VERSION 5.7 ;
BUSBITCHARS "[]" ;
DIVIDERCHAR "/" ;

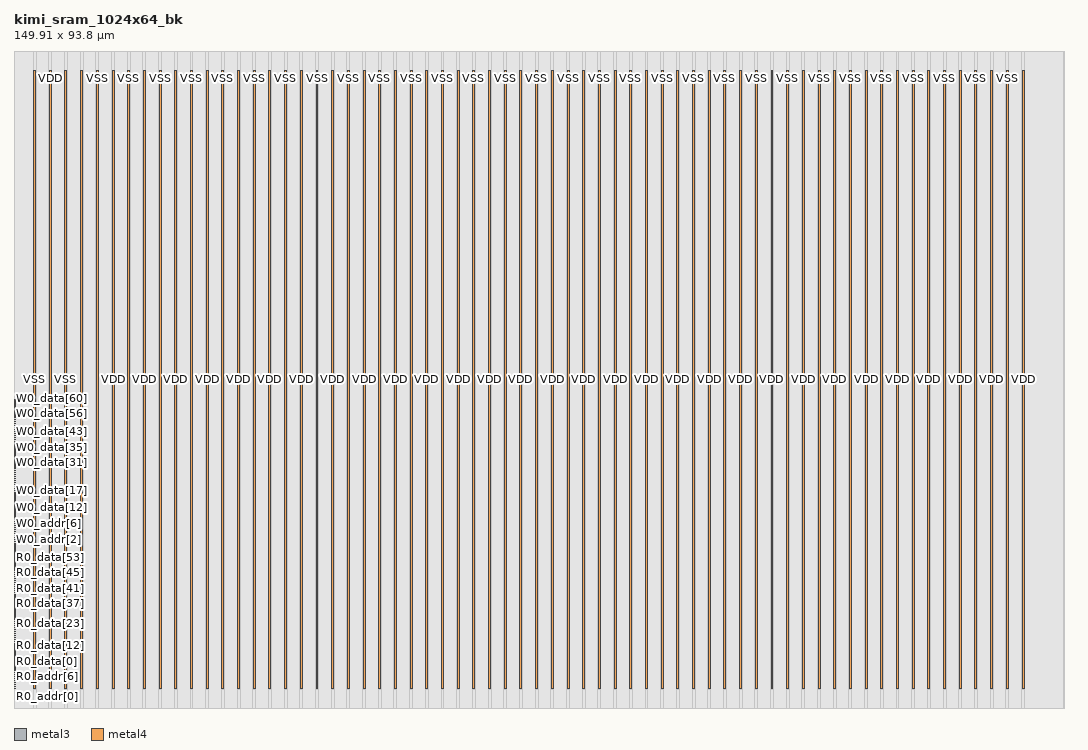
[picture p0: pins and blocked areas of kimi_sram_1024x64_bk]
MACRO kimi_sram_1024x64_bk
  CLASS BLOCK ;
  FOREIGN kimi_sram_1024x64_bk 0 0 ;
  ORIGIN 0 0 ;
  SIZE 149.91 BY 93.8 ;
  SYMMETRY X Y R90 ;
  PIN R0_addr[0]
    DIRECTION INPUT ;
    USE SIGNAL ;
    PORT
      LAYER metal3 ;
      RECT 0.0 2.765 0.19 2.835 ;
    END
  END R0_addr[0]
  PIN R0_addr[1]
    DIRECTION INPUT ;
    USE SIGNAL ;
    PORT
      LAYER metal3 ;
      RECT 0.0 3.045 0.19 3.115 ;
    END
  END R0_addr[1]
  PIN R0_addr[2]
    DIRECTION INPUT ;
    USE SIGNAL ;
    PORT
      LAYER metal3 ;
      RECT 0.0 3.325 0.19 3.395 ;
    END
  END R0_addr[2]
  PIN R0_addr[3]
    DIRECTION INPUT ;
    USE SIGNAL ;
    PORT
      LAYER metal3 ;
      RECT 0.0 3.605 0.19 3.675 ;
    END
  END R0_addr[3]
  PIN R0_addr[4]
    DIRECTION INPUT ;
    USE SIGNAL ;
    PORT
      LAYER metal3 ;
      RECT 0.0 3.885 0.19 3.955 ;
    END
  END R0_addr[4]
  PIN R0_addr[5]
    DIRECTION INPUT ;
    USE SIGNAL ;
    PORT
      LAYER metal3 ;
      RECT 0.0 4.165 0.19 4.235 ;
    END
  END R0_addr[5]
  PIN R0_addr[6]
    DIRECTION INPUT ;
    USE SIGNAL ;
    PORT
      LAYER metal3 ;
      RECT 0.0 4.445 0.19 4.515 ;
    END
  END R0_addr[6]
  PIN R0_addr[7]
    DIRECTION INPUT ;
    USE SIGNAL ;
    PORT
      LAYER metal3 ;
      RECT 0.0 4.725 0.19 4.795 ;
    END
  END R0_addr[7]
  PIN R0_clk
    DIRECTION INPUT ;
    USE SIGNAL ;
    PORT
      LAYER metal3 ;
      RECT 0.0 5.005 0.19 5.075 ;
    END
  END R0_clk
  PIN R0_en
    DIRECTION INPUT ;
    USE SIGNAL ;
    PORT
      LAYER metal3 ;
      RECT 0.0 5.285 0.19 5.355 ;
    END
  END R0_en
  PIN R0_data[0]
    DIRECTION OUTPUT ;
    USE SIGNAL ;
    PORT
      LAYER metal3 ;
      RECT 0.0 5.565 0.19 5.635 ;
    END
  END R0_data[0]
  PIN R0_data[1]
    DIRECTION OUTPUT ;
    USE SIGNAL ;
    PORT
      LAYER metal3 ;
      RECT 0.0 5.845 0.19 5.915 ;
    END
  END R0_data[1]
  PIN R0_data[2]
    DIRECTION OUTPUT ;
    USE SIGNAL ;
    PORT
      LAYER metal3 ;
      RECT 0.0 6.125 0.19 6.195 ;
    END
  END R0_data[2]
  PIN R0_data[3]
    DIRECTION OUTPUT ;
    USE SIGNAL ;
    PORT
      LAYER metal3 ;
      RECT 0.0 6.405 0.19 6.475 ;
    END
  END R0_data[3]
  PIN R0_data[4]
    DIRECTION OUTPUT ;
    USE SIGNAL ;
    PORT
      LAYER metal3 ;
      RECT 0.0 6.685 0.19 6.755 ;
    END
  END R0_data[4]
  PIN R0_data[5]
    DIRECTION OUTPUT ;
    USE SIGNAL ;
    PORT
      LAYER metal3 ;
      RECT 0.0 6.965 0.19 7.035 ;
    END
  END R0_data[5]
  PIN R0_data[6]
    DIRECTION OUTPUT ;
    USE SIGNAL ;
    PORT
      LAYER metal3 ;
      RECT 0.0 7.245 0.19 7.315 ;
    END
  END R0_data[6]
  PIN R0_data[7]
    DIRECTION OUTPUT ;
    USE SIGNAL ;
    PORT
      LAYER metal3 ;
      RECT 0.0 7.525 0.19 7.595 ;
    END
  END R0_data[7]
  PIN R0_data[8]
    DIRECTION OUTPUT ;
    USE SIGNAL ;
    PORT
      LAYER metal3 ;
      RECT 0.0 7.805 0.19 7.875 ;
    END
  END R0_data[8]
  PIN R0_data[9]
    DIRECTION OUTPUT ;
    USE SIGNAL ;
    PORT
      LAYER metal3 ;
      RECT 0.0 8.085 0.19 8.155 ;
    END
  END R0_data[9]
  PIN R0_data[10]
    DIRECTION OUTPUT ;
    USE SIGNAL ;
    PORT
      LAYER metal3 ;
      RECT 0.0 8.365 0.19 8.435 ;
    END
  END R0_data[10]
  PIN R0_data[11]
    DIRECTION OUTPUT ;
    USE SIGNAL ;
    PORT
      LAYER metal3 ;
      RECT 0.0 8.645 0.19 8.715 ;
    END
  END R0_data[11]
  PIN R0_data[12]
    DIRECTION OUTPUT ;
    USE SIGNAL ;
    PORT
      LAYER metal3 ;
      RECT 0.0 8.925 0.19 8.995 ;
    END
  END R0_data[12]
  PIN R0_data[13]
    DIRECTION OUTPUT ;
    USE SIGNAL ;
    PORT
      LAYER metal3 ;
      RECT 0.0 9.205 0.19 9.275 ;
    END
  END R0_data[13]
  PIN R0_data[14]
    DIRECTION OUTPUT ;
    USE SIGNAL ;
    PORT
      LAYER metal3 ;
      RECT 0.0 9.485 0.19 9.555 ;
    END
  END R0_data[14]
  PIN R0_data[15]
    DIRECTION OUTPUT ;
    USE SIGNAL ;
    PORT
      LAYER metal3 ;
      RECT 0.0 9.765 0.19 9.835 ;
    END
  END R0_data[15]
  PIN R0_data[16]
    DIRECTION OUTPUT ;
    USE SIGNAL ;
    PORT
      LAYER metal3 ;
      RECT 0.0 10.045 0.19 10.115 ;
    END
  END R0_data[16]
  PIN R0_data[17]
    DIRECTION OUTPUT ;
    USE SIGNAL ;
    PORT
      LAYER metal3 ;
      RECT 0.0 10.325 0.19 10.395 ;
    END
  END R0_data[17]
  PIN R0_data[18]
    DIRECTION OUTPUT ;
    USE SIGNAL ;
    PORT
      LAYER metal3 ;
      RECT 0.0 10.605 0.19 10.675 ;
    END
  END R0_data[18]
  PIN R0_data[19]
    DIRECTION OUTPUT ;
    USE SIGNAL ;
    PORT
      LAYER metal3 ;
      RECT 0.0 10.885 0.19 10.955 ;
    END
  END R0_data[19]
  PIN R0_data[20]
    DIRECTION OUTPUT ;
    USE SIGNAL ;
    PORT
      LAYER metal3 ;
      RECT 0.0 11.165 0.19 11.235 ;
    END
  END R0_data[20]
  PIN R0_data[21]
    DIRECTION OUTPUT ;
    USE SIGNAL ;
    PORT
      LAYER metal3 ;
      RECT 0.0 11.445 0.19 11.515 ;
    END
  END R0_data[21]
  PIN R0_data[22]
    DIRECTION OUTPUT ;
    USE SIGNAL ;
    PORT
      LAYER metal3 ;
      RECT 0.0 11.725 0.19 11.795 ;
    END
  END R0_data[22]
  PIN R0_data[23]
    DIRECTION OUTPUT ;
    USE SIGNAL ;
    PORT
      LAYER metal3 ;
      RECT 0.0 12.005 0.19 12.075 ;
    END
  END R0_data[23]
  PIN R0_data[24]
    DIRECTION OUTPUT ;
    USE SIGNAL ;
    PORT
      LAYER metal3 ;
      RECT 0.0 12.285 0.19 12.355 ;
    END
  END R0_data[24]
  PIN R0_data[25]
    DIRECTION OUTPUT ;
    USE SIGNAL ;
    PORT
      LAYER metal3 ;
      RECT 0.0 12.565 0.19 12.635 ;
    END
  END R0_data[25]
  PIN R0_data[26]
    DIRECTION OUTPUT ;
    USE SIGNAL ;
    PORT
      LAYER metal3 ;
      RECT 0.0 12.845 0.19 12.915 ;
    END
  END R0_data[26]
  PIN R0_data[27]
    DIRECTION OUTPUT ;
    USE SIGNAL ;
    PORT
      LAYER metal3 ;
      RECT 0.0 13.125 0.19 13.195 ;
    END
  END R0_data[27]
  PIN R0_data[28]
    DIRECTION OUTPUT ;
    USE SIGNAL ;
    PORT
      LAYER metal3 ;
      RECT 0.0 13.405 0.19 13.475 ;
    END
  END R0_data[28]
  PIN R0_data[29]
    DIRECTION OUTPUT ;
    USE SIGNAL ;
    PORT
      LAYER metal3 ;
      RECT 0.0 13.685 0.19 13.755 ;
    END
  END R0_data[29]
  PIN R0_data[30]
    DIRECTION OUTPUT ;
    USE SIGNAL ;
    PORT
      LAYER metal3 ;
      RECT 0.0 13.965 0.19 14.035 ;
    END
  END R0_data[30]
  PIN R0_data[31]
    DIRECTION OUTPUT ;
    USE SIGNAL ;
    PORT
      LAYER metal3 ;
      RECT 0.0 14.245 0.19 14.315 ;
    END
  END R0_data[31]
  PIN R0_data[32]
    DIRECTION OUTPUT ;
    USE SIGNAL ;
    PORT
      LAYER metal3 ;
      RECT 0.0 14.525 0.19 14.595 ;
    END
  END R0_data[32]
  PIN R0_data[33]
    DIRECTION OUTPUT ;
    USE SIGNAL ;
    PORT
      LAYER metal3 ;
      RECT 0.0 14.805 0.19 14.875 ;
    END
  END R0_data[33]
  PIN R0_data[34]
    DIRECTION OUTPUT ;
    USE SIGNAL ;
    PORT
      LAYER metal3 ;
      RECT 0.0 15.085 0.19 15.155 ;
    END
  END R0_data[34]
  PIN R0_data[35]
    DIRECTION OUTPUT ;
    USE SIGNAL ;
    PORT
      LAYER metal3 ;
      RECT 0.0 15.365 0.19 15.435 ;
    END
  END R0_data[35]
  PIN R0_data[36]
    DIRECTION OUTPUT ;
    USE SIGNAL ;
    PORT
      LAYER metal3 ;
      RECT 0.0 15.645 0.19 15.715 ;
    END
  END R0_data[36]
  PIN R0_data[37]
    DIRECTION OUTPUT ;
    USE SIGNAL ;
    PORT
      LAYER metal3 ;
      RECT 0.0 15.925 0.19 15.995 ;
    END
  END R0_data[37]
  PIN R0_data[38]
    DIRECTION OUTPUT ;
    USE SIGNAL ;
    PORT
      LAYER metal3 ;
      RECT 0.0 16.205 0.19 16.275 ;
    END
  END R0_data[38]
  PIN R0_data[39]
    DIRECTION OUTPUT ;
    USE SIGNAL ;
    PORT
      LAYER metal3 ;
      RECT 0.0 16.485 0.19 16.555 ;
    END
  END R0_data[39]
  PIN R0_data[40]
    DIRECTION OUTPUT ;
    USE SIGNAL ;
    PORT
      LAYER metal3 ;
      RECT 0.0 16.765 0.19 16.835 ;
    END
  END R0_data[40]
  PIN R0_data[41]
    DIRECTION OUTPUT ;
    USE SIGNAL ;
    PORT
      LAYER metal3 ;
      RECT 0.0 17.045 0.19 17.115 ;
    END
  END R0_data[41]
  PIN R0_data[42]
    DIRECTION OUTPUT ;
    USE SIGNAL ;
    PORT
      LAYER metal3 ;
      RECT 0.0 17.325 0.19 17.395 ;
    END
  END R0_data[42]
  PIN R0_data[43]
    DIRECTION OUTPUT ;
    USE SIGNAL ;
    PORT
      LAYER metal3 ;
      RECT 0.0 17.605 0.19 17.675 ;
    END
  END R0_data[43]
  PIN R0_data[44]
    DIRECTION OUTPUT ;
    USE SIGNAL ;
    PORT
      LAYER metal3 ;
      RECT 0.0 17.885 0.19 17.955 ;
    END
  END R0_data[44]
  PIN R0_data[45]
    DIRECTION OUTPUT ;
    USE SIGNAL ;
    PORT
      LAYER metal3 ;
      RECT 0.0 18.165 0.19 18.235 ;
    END
  END R0_data[45]
  PIN R0_data[46]
    DIRECTION OUTPUT ;
    USE SIGNAL ;
    PORT
      LAYER metal3 ;
      RECT 0.0 18.445 0.19 18.515 ;
    END
  END R0_data[46]
  PIN R0_data[47]
    DIRECTION OUTPUT ;
    USE SIGNAL ;
    PORT
      LAYER metal3 ;
      RECT 0.0 18.725 0.19 18.795 ;
    END
  END R0_data[47]
  PIN R0_data[48]
    DIRECTION OUTPUT ;
    USE SIGNAL ;
    PORT
      LAYER metal3 ;
      RECT 0.0 19.005 0.19 19.075 ;
    END
  END R0_data[48]
  PIN R0_data[49]
    DIRECTION OUTPUT ;
    USE SIGNAL ;
    PORT
      LAYER metal3 ;
      RECT 0.0 19.285 0.19 19.355 ;
    END
  END R0_data[49]
  PIN R0_data[50]
    DIRECTION OUTPUT ;
    USE SIGNAL ;
    PORT
      LAYER metal3 ;
      RECT 0.0 19.565 0.19 19.635 ;
    END
  END R0_data[50]
  PIN R0_data[51]
    DIRECTION OUTPUT ;
    USE SIGNAL ;
    PORT
      LAYER metal3 ;
      RECT 0.0 19.845 0.19 19.915 ;
    END
  END R0_data[51]
  PIN R0_data[52]
    DIRECTION OUTPUT ;
    USE SIGNAL ;
    PORT
      LAYER metal3 ;
      RECT 0.0 20.125 0.19 20.195 ;
    END
  END R0_data[52]
  PIN R0_data[53]
    DIRECTION OUTPUT ;
    USE SIGNAL ;
    PORT
      LAYER metal3 ;
      RECT 0.0 20.405 0.19 20.475 ;
    END
  END R0_data[53]
  PIN R0_data[54]
    DIRECTION OUTPUT ;
    USE SIGNAL ;
    PORT
      LAYER metal3 ;
      RECT 0.0 20.685 0.19 20.755 ;
    END
  END R0_data[54]
  PIN R0_data[55]
    DIRECTION OUTPUT ;
    USE SIGNAL ;
    PORT
      LAYER metal3 ;
      RECT 0.0 20.965 0.19 21.035 ;
    END
  END R0_data[55]
  PIN R0_data[56]
    DIRECTION OUTPUT ;
    USE SIGNAL ;
    PORT
      LAYER metal3 ;
      RECT 0.0 21.245 0.19 21.315 ;
    END
  END R0_data[56]
  PIN R0_data[57]
    DIRECTION OUTPUT ;
    USE SIGNAL ;
    PORT
      LAYER metal3 ;
      RECT 0.0 21.525 0.19 21.595 ;
    END
  END R0_data[57]
  PIN R0_data[58]
    DIRECTION OUTPUT ;
    USE SIGNAL ;
    PORT
      LAYER metal3 ;
      RECT 0.0 21.805 0.19 21.875 ;
    END
  END R0_data[58]
  PIN R0_data[59]
    DIRECTION OUTPUT ;
    USE SIGNAL ;
    PORT
      LAYER metal3 ;
      RECT 0.0 22.085 0.19 22.155 ;
    END
  END R0_data[59]
  PIN R0_data[60]
    DIRECTION OUTPUT ;
    USE SIGNAL ;
    PORT
      LAYER metal3 ;
      RECT 0.0 22.365 0.19 22.435 ;
    END
  END R0_data[60]
  PIN R0_data[61]
    DIRECTION OUTPUT ;
    USE SIGNAL ;
    PORT
      LAYER metal3 ;
      RECT 0.0 22.645 0.19 22.715 ;
    END
  END R0_data[61]
  PIN R0_data[62]
    DIRECTION OUTPUT ;
    USE SIGNAL ;
    PORT
      LAYER metal3 ;
      RECT 0.0 22.925 0.19 22.995 ;
    END
  END R0_data[62]
  PIN R0_data[63]
    DIRECTION OUTPUT ;
    USE SIGNAL ;
    PORT
      LAYER metal3 ;
      RECT 0.0 23.205 0.19 23.275 ;
    END
  END R0_data[63]
  PIN W0_addr[0]
    DIRECTION INPUT ;
    USE SIGNAL ;
    PORT
      LAYER metal3 ;
      RECT 0.0 23.485 0.19 23.555 ;
    END
  END W0_addr[0]
  PIN W0_addr[1]
    DIRECTION INPUT ;
    USE SIGNAL ;
    PORT
      LAYER metal3 ;
      RECT 0.0 23.765 0.19 23.835 ;
    END
  END W0_addr[1]
  PIN W0_addr[2]
    DIRECTION INPUT ;
    USE SIGNAL ;
    PORT
      LAYER metal3 ;
      RECT 0.0 24.045 0.19 24.115 ;
    END
  END W0_addr[2]
  PIN W0_addr[3]
    DIRECTION INPUT ;
    USE SIGNAL ;
    PORT
      LAYER metal3 ;
      RECT 0.0 24.325 0.19 24.395 ;
    END
  END W0_addr[3]
  PIN W0_addr[4]
    DIRECTION INPUT ;
    USE SIGNAL ;
    PORT
      LAYER metal3 ;
      RECT 0.0 24.605 0.19 24.675 ;
    END
  END W0_addr[4]
  PIN W0_addr[5]
    DIRECTION INPUT ;
    USE SIGNAL ;
    PORT
      LAYER metal3 ;
      RECT 0.0 24.885 0.19 24.955 ;
    END
  END W0_addr[5]
  PIN W0_addr[6]
    DIRECTION INPUT ;
    USE SIGNAL ;
    PORT
      LAYER metal3 ;
      RECT 0.0 25.165 0.19 25.235 ;
    END
  END W0_addr[6]
  PIN W0_addr[7]
    DIRECTION INPUT ;
    USE SIGNAL ;
    PORT
      LAYER metal3 ;
      RECT 0.0 25.445 0.19 25.515 ;
    END
  END W0_addr[7]
  PIN W0_en
    DIRECTION INPUT ;
    USE SIGNAL ;
    PORT
      LAYER metal3 ;
      RECT 0.0 25.725 0.19 25.795 ;
    END
  END W0_en
  PIN W0_clk
    DIRECTION INPUT ;
    USE SIGNAL ;
    PORT
      LAYER metal3 ;
      RECT 0.0 26.005 0.19 26.075 ;
    END
  END W0_clk
  PIN W0_data[0]
    DIRECTION INPUT ;
    USE SIGNAL ;
    PORT
      LAYER metal3 ;
      RECT 0.0 26.285 0.19 26.355 ;
    END
  END W0_data[0]
  PIN W0_data[1]
    DIRECTION INPUT ;
    USE SIGNAL ;
    PORT
      LAYER metal3 ;
      RECT 0.0 26.565 0.19 26.635 ;
    END
  END W0_data[1]
  PIN W0_data[2]
    DIRECTION INPUT ;
    USE SIGNAL ;
    PORT
      LAYER metal3 ;
      RECT 0.0 26.845 0.19 26.915 ;
    END
  END W0_data[2]
  PIN W0_data[3]
    DIRECTION INPUT ;
    USE SIGNAL ;
    PORT
      LAYER metal3 ;
      RECT 0.0 27.125 0.19 27.195 ;
    END
  END W0_data[3]
  PIN W0_data[4]
    DIRECTION INPUT ;
    USE SIGNAL ;
    PORT
      LAYER metal3 ;
      RECT 0.0 27.405 0.19 27.475 ;
    END
  END W0_data[4]
  PIN W0_data[5]
    DIRECTION INPUT ;
    USE SIGNAL ;
    PORT
      LAYER metal3 ;
      RECT 0.0 27.685 0.19 27.755 ;
    END
  END W0_data[5]
  PIN W0_data[6]
    DIRECTION INPUT ;
    USE SIGNAL ;
    PORT
      LAYER metal3 ;
      RECT 0.0 27.965 0.19 28.035 ;
    END
  END W0_data[6]
  PIN W0_data[7]
    DIRECTION INPUT ;
    USE SIGNAL ;
    PORT
      LAYER metal3 ;
      RECT 0.0 28.245 0.19 28.315 ;
    END
  END W0_data[7]
  PIN W0_data[8]
    DIRECTION INPUT ;
    USE SIGNAL ;
    PORT
      LAYER metal3 ;
      RECT 0.0 28.525 0.19 28.595 ;
    END
  END W0_data[8]
  PIN W0_data[9]
    DIRECTION INPUT ;
    USE SIGNAL ;
    PORT
      LAYER metal3 ;
      RECT 0.0 28.805 0.19 28.875 ;
    END
  END W0_data[9]
  PIN W0_data[10]
    DIRECTION INPUT ;
    USE SIGNAL ;
    PORT
      LAYER metal3 ;
      RECT 0.0 29.085 0.19 29.155 ;
    END
  END W0_data[10]
  PIN W0_data[11]
    DIRECTION INPUT ;
    USE SIGNAL ;
    PORT
      LAYER metal3 ;
      RECT 0.0 29.365 0.19 29.435 ;
    END
  END W0_data[11]
  PIN W0_data[12]
    DIRECTION INPUT ;
    USE SIGNAL ;
    PORT
      LAYER metal3 ;
      RECT 0.0 29.645 0.19 29.715 ;
    END
  END W0_data[12]
  PIN W0_data[13]
    DIRECTION INPUT ;
    USE SIGNAL ;
    PORT
      LAYER metal3 ;
      RECT 0.0 29.925 0.19 29.995 ;
    END
  END W0_data[13]
  PIN W0_data[14]
    DIRECTION INPUT ;
    USE SIGNAL ;
    PORT
      LAYER metal3 ;
      RECT 0.0 30.205 0.19 30.275 ;
    END
  END W0_data[14]
  PIN W0_data[15]
    DIRECTION INPUT ;
    USE SIGNAL ;
    PORT
      LAYER metal3 ;
      RECT 0.0 30.485 0.19 30.555 ;
    END
  END W0_data[15]
  PIN W0_data[16]
    DIRECTION INPUT ;
    USE SIGNAL ;
    PORT
      LAYER metal3 ;
      RECT 0.0 30.765 0.19 30.835 ;
    END
  END W0_data[16]
  PIN W0_data[17]
    DIRECTION INPUT ;
    USE SIGNAL ;
    PORT
      LAYER metal3 ;
      RECT 0.0 31.045 0.19 31.115 ;
    END
  END W0_data[17]
  PIN W0_data[18]
    DIRECTION INPUT ;
    USE SIGNAL ;
    PORT
      LAYER metal3 ;
      RECT 0.0 31.325 0.19 31.395 ;
    END
  END W0_data[18]
  PIN W0_data[19]
    DIRECTION INPUT ;
    USE SIGNAL ;
    PORT
      LAYER metal3 ;
      RECT 0.0 31.605 0.19 31.675 ;
    END
  END W0_data[19]
  PIN W0_data[20]
    DIRECTION INPUT ;
    USE SIGNAL ;
    PORT
      LAYER metal3 ;
      RECT 0.0 31.885 0.19 31.955 ;
    END
  END W0_data[20]
  PIN W0_data[21]
    DIRECTION INPUT ;
    USE SIGNAL ;
    PORT
      LAYER metal3 ;
      RECT 0.0 32.165 0.19 32.235 ;
    END
  END W0_data[21]
  PIN W0_data[22]
    DIRECTION INPUT ;
    USE SIGNAL ;
    PORT
      LAYER metal3 ;
      RECT 0.0 32.445 0.19 32.515 ;
    END
  END W0_data[22]
  PIN W0_data[23]
    DIRECTION INPUT ;
    USE SIGNAL ;
    PORT
      LAYER metal3 ;
      RECT 0.0 32.725 0.19 32.795 ;
    END
  END W0_data[23]
  PIN W0_data[24]
    DIRECTION INPUT ;
    USE SIGNAL ;
    PORT
      LAYER metal3 ;
      RECT 0.0 33.005 0.19 33.075 ;
    END
  END W0_data[24]
  PIN W0_data[25]
    DIRECTION INPUT ;
    USE SIGNAL ;
    PORT
      LAYER metal3 ;
      RECT 0.0 33.285 0.19 33.355 ;
    END
  END W0_data[25]
  PIN W0_data[26]
    DIRECTION INPUT ;
    USE SIGNAL ;
    PORT
      LAYER metal3 ;
      RECT 0.0 33.565 0.19 33.635 ;
    END
  END W0_data[26]
  PIN W0_data[27]
    DIRECTION INPUT ;
    USE SIGNAL ;
    PORT
      LAYER metal3 ;
      RECT 0.0 33.845 0.19 33.915 ;
    END
  END W0_data[27]
  PIN W0_data[28]
    DIRECTION INPUT ;
    USE SIGNAL ;
    PORT
      LAYER metal3 ;
      RECT 0.0 34.125 0.19 34.195 ;
    END
  END W0_data[28]
  PIN W0_data[29]
    DIRECTION INPUT ;
    USE SIGNAL ;
    PORT
      LAYER metal3 ;
      RECT 0.0 34.405 0.19 34.475 ;
    END
  END W0_data[29]
  PIN W0_data[30]
    DIRECTION INPUT ;
    USE SIGNAL ;
    PORT
      LAYER metal3 ;
      RECT 0.0 34.685 0.19 34.755 ;
    END
  END W0_data[30]
  PIN W0_data[31]
    DIRECTION INPUT ;
    USE SIGNAL ;
    PORT
      LAYER metal3 ;
      RECT 0.0 34.965 0.19 35.035 ;
    END
  END W0_data[31]
  PIN W0_data[32]
    DIRECTION INPUT ;
    USE SIGNAL ;
    PORT
      LAYER metal3 ;
      RECT 0.0 35.245 0.19 35.315 ;
    END
  END W0_data[32]
  PIN W0_data[33]
    DIRECTION INPUT ;
    USE SIGNAL ;
    PORT
      LAYER metal3 ;
      RECT 0.0 35.525 0.19 35.595 ;
    END
  END W0_data[33]
  PIN W0_data[34]
    DIRECTION INPUT ;
    USE SIGNAL ;
    PORT
      LAYER metal3 ;
      RECT 0.0 35.805 0.19 35.875 ;
    END
  END W0_data[34]
  PIN W0_data[35]
    DIRECTION INPUT ;
    USE SIGNAL ;
    PORT
      LAYER metal3 ;
      RECT 0.0 36.085 0.19 36.155 ;
    END
  END W0_data[35]
  PIN W0_data[36]
    DIRECTION INPUT ;
    USE SIGNAL ;
    PORT
      LAYER metal3 ;
      RECT 0.0 36.365 0.19 36.435 ;
    END
  END W0_data[36]
  PIN W0_data[37]
    DIRECTION INPUT ;
    USE SIGNAL ;
    PORT
      LAYER metal3 ;
      RECT 0.0 36.645 0.19 36.715 ;
    END
  END W0_data[37]
  PIN W0_data[38]
    DIRECTION INPUT ;
    USE SIGNAL ;
    PORT
      LAYER metal3 ;
      RECT 0.0 36.925 0.19 36.995 ;
    END
  END W0_data[38]
  PIN W0_data[39]
    DIRECTION INPUT ;
    USE SIGNAL ;
    PORT
      LAYER metal3 ;
      RECT 0.0 37.205 0.19 37.275 ;
    END
  END W0_data[39]
  PIN W0_data[40]
    DIRECTION INPUT ;
    USE SIGNAL ;
    PORT
      LAYER metal3 ;
      RECT 0.0 37.485 0.19 37.555 ;
    END
  END W0_data[40]
  PIN W0_data[41]
    DIRECTION INPUT ;
    USE SIGNAL ;
    PORT
      LAYER metal3 ;
      RECT 0.0 37.765 0.19 37.835 ;
    END
  END W0_data[41]
  PIN W0_data[42]
    DIRECTION INPUT ;
    USE SIGNAL ;
    PORT
      LAYER metal3 ;
      RECT 0.0 38.045 0.19 38.115 ;
    END
  END W0_data[42]
  PIN W0_data[43]
    DIRECTION INPUT ;
    USE SIGNAL ;
    PORT
      LAYER metal3 ;
      RECT 0.0 38.325 0.19 38.395 ;
    END
  END W0_data[43]
  PIN W0_data[44]
    DIRECTION INPUT ;
    USE SIGNAL ;
    PORT
      LAYER metal3 ;
      RECT 0.0 38.605 0.19 38.675 ;
    END
  END W0_data[44]
  PIN W0_data[45]
    DIRECTION INPUT ;
    USE SIGNAL ;
    PORT
      LAYER metal3 ;
      RECT 0.0 38.885 0.19 38.955 ;
    END
  END W0_data[45]
  PIN W0_data[46]
    DIRECTION INPUT ;
    USE SIGNAL ;
    PORT
      LAYER metal3 ;
      RECT 0.0 39.165 0.19 39.235 ;
    END
  END W0_data[46]
  PIN W0_data[47]
    DIRECTION INPUT ;
    USE SIGNAL ;
    PORT
      LAYER metal3 ;
      RECT 0.0 39.445 0.19 39.515 ;
    END
  END W0_data[47]
  PIN W0_data[48]
    DIRECTION INPUT ;
    USE SIGNAL ;
    PORT
      LAYER metal3 ;
      RECT 0.0 39.725 0.19 39.795 ;
    END
  END W0_data[48]
  PIN W0_data[49]
    DIRECTION INPUT ;
    USE SIGNAL ;
    PORT
      LAYER metal3 ;
      RECT 0.0 40.005 0.19 40.075 ;
    END
  END W0_data[49]
  PIN W0_data[50]
    DIRECTION INPUT ;
    USE SIGNAL ;
    PORT
      LAYER metal3 ;
      RECT 0.0 40.285 0.19 40.355 ;
    END
  END W0_data[50]
  PIN W0_data[51]
    DIRECTION INPUT ;
    USE SIGNAL ;
    PORT
      LAYER metal3 ;
      RECT 0.0 40.565 0.19 40.635 ;
    END
  END W0_data[51]
  PIN W0_data[52]
    DIRECTION INPUT ;
    USE SIGNAL ;
    PORT
      LAYER metal3 ;
      RECT 0.0 40.845 0.19 40.915 ;
    END
  END W0_data[52]
  PIN W0_data[53]
    DIRECTION INPUT ;
    USE SIGNAL ;
    PORT
      LAYER metal3 ;
      RECT 0.0 41.125 0.19 41.195 ;
    END
  END W0_data[53]
  PIN W0_data[54]
    DIRECTION INPUT ;
    USE SIGNAL ;
    PORT
      LAYER metal3 ;
      RECT 0.0 41.405 0.19 41.475 ;
    END
  END W0_data[54]
  PIN W0_data[55]
    DIRECTION INPUT ;
    USE SIGNAL ;
    PORT
      LAYER metal3 ;
      RECT 0.0 41.685 0.19 41.755 ;
    END
  END W0_data[55]
  PIN W0_data[56]
    DIRECTION INPUT ;
    USE SIGNAL ;
    PORT
      LAYER metal3 ;
      RECT 0.0 41.965 0.19 42.035 ;
    END
  END W0_data[56]
  PIN W0_data[57]
    DIRECTION INPUT ;
    USE SIGNAL ;
    PORT
      LAYER metal3 ;
      RECT 0.0 42.245 0.19 42.315 ;
    END
  END W0_data[57]
  PIN W0_data[58]
    DIRECTION INPUT ;
    USE SIGNAL ;
    PORT
      LAYER metal3 ;
      RECT 0.0 42.525 0.19 42.595 ;
    END
  END W0_data[58]
  PIN W0_data[59]
    DIRECTION INPUT ;
    USE SIGNAL ;
    PORT
      LAYER metal3 ;
      RECT 0.0 42.805 0.19 42.875 ;
    END
  END W0_data[59]
  PIN W0_data[60]
    DIRECTION INPUT ;
    USE SIGNAL ;
    PORT
      LAYER metal3 ;
      RECT 0.0 43.085 0.19 43.155 ;
    END
  END W0_data[60]
  PIN W0_data[61]
    DIRECTION INPUT ;
    USE SIGNAL ;
    PORT
      LAYER metal3 ;
      RECT 0.0 43.365 0.19 43.435 ;
    END
  END W0_data[61]
  PIN W0_data[62]
    DIRECTION INPUT ;
    USE SIGNAL ;
    PORT
      LAYER metal3 ;
      RECT 0.0 43.645 0.19 43.715 ;
    END
  END W0_data[62]
  PIN W0_data[63]
    DIRECTION INPUT ;
    USE SIGNAL ;
    PORT
      LAYER metal3 ;
      RECT 0.0 43.925 0.19 43.995 ;
    END
  END W0_data[63]
  PIN VSS
    DIRECTION INOUT ;
    USE GROUND ;
    PORT
      LAYER metal4 ;
      RECT 2.8 2.8 3.08 91.0 ;
    END
  END VSS
  PIN VDD
    DIRECTION INOUT ;
    USE POWER ;
    PORT
      LAYER metal4 ;
      RECT 5.04 2.8 5.32 91.0 ;
    END
  END VDD
  PIN VSS
    DIRECTION INOUT ;
    USE GROUND ;
    PORT
      LAYER metal4 ;
      RECT 7.28 2.8 7.56 91.0 ;
    END
  END VSS
  PIN VDD
    DIRECTION INOUT ;
    USE POWER ;
    PORT
      LAYER metal4 ;
      RECT 9.52 2.8 9.8 91.0 ;
    END
  END VDD
  PIN VSS
    DIRECTION INOUT ;
    USE GROUND ;
    PORT
      LAYER metal4 ;
      RECT 11.76 2.8 12.04 91.0 ;
    END
  END VSS
  PIN VDD
    DIRECTION INOUT ;
    USE POWER ;
    PORT
      LAYER metal4 ;
      RECT 14.0 2.8 14.28 91.0 ;
    END
  END VDD
  PIN VSS
    DIRECTION INOUT ;
    USE GROUND ;
    PORT
      LAYER metal4 ;
      RECT 16.24 2.8 16.52 91.0 ;
    END
  END VSS
  PIN VDD
    DIRECTION INOUT ;
    USE POWER ;
    PORT
      LAYER metal4 ;
      RECT 18.48 2.8 18.76 91.0 ;
    END
  END VDD
  PIN VSS
    DIRECTION INOUT ;
    USE GROUND ;
    PORT
      LAYER metal4 ;
      RECT 20.72 2.8 21.0 91.0 ;
    END
  END VSS
  PIN VDD
    DIRECTION INOUT ;
    USE POWER ;
    PORT
      LAYER metal4 ;
      RECT 22.96 2.8 23.24 91.0 ;
    END
  END VDD
  PIN VSS
    DIRECTION INOUT ;
    USE GROUND ;
    PORT
      LAYER metal4 ;
      RECT 25.2 2.8 25.48 91.0 ;
    END
  END VSS
  PIN VDD
    DIRECTION INOUT ;
    USE POWER ;
    PORT
      LAYER metal4 ;
      RECT 27.44 2.8 27.72 91.0 ;
    END
  END VDD
  PIN VSS
    DIRECTION INOUT ;
    USE GROUND ;
    PORT
      LAYER metal4 ;
      RECT 29.68 2.8 29.96 91.0 ;
    END
  END VSS
  PIN VDD
    DIRECTION INOUT ;
    USE POWER ;
    PORT
      LAYER metal4 ;
      RECT 31.92 2.8 32.2 91.0 ;
    END
  END VDD
  PIN VSS
    DIRECTION INOUT ;
    USE GROUND ;
    PORT
      LAYER metal4 ;
      RECT 34.16 2.8 34.44 91.0 ;
    END
  END VSS
  PIN VDD
    DIRECTION INOUT ;
    USE POWER ;
    PORT
      LAYER metal4 ;
      RECT 36.4 2.8 36.68 91.0 ;
    END
  END VDD
  PIN VSS
    DIRECTION INOUT ;
    USE GROUND ;
    PORT
      LAYER metal4 ;
      RECT 38.64 2.8 38.92 91.0 ;
    END
  END VSS
  PIN VDD
    DIRECTION INOUT ;
    USE POWER ;
    PORT
      LAYER metal4 ;
      RECT 40.88 2.8 41.16 91.0 ;
    END
  END VDD
  PIN VSS
    DIRECTION INOUT ;
    USE GROUND ;
    PORT
      LAYER metal4 ;
      RECT 43.12 2.8 43.4 91.0 ;
    END
  END VSS
  PIN VDD
    DIRECTION INOUT ;
    USE POWER ;
    PORT
      LAYER metal4 ;
      RECT 45.36 2.8 45.64 91.0 ;
    END
  END VDD
  PIN VSS
    DIRECTION INOUT ;
    USE GROUND ;
    PORT
      LAYER metal4 ;
      RECT 47.6 2.8 47.88 91.0 ;
    END
  END VSS
  PIN VDD
    DIRECTION INOUT ;
    USE POWER ;
    PORT
      LAYER metal4 ;
      RECT 49.84 2.8 50.12 91.0 ;
    END
  END VDD
  PIN VSS
    DIRECTION INOUT ;
    USE GROUND ;
    PORT
      LAYER metal4 ;
      RECT 52.08 2.8 52.36 91.0 ;
    END
  END VSS
  PIN VDD
    DIRECTION INOUT ;
    USE POWER ;
    PORT
      LAYER metal4 ;
      RECT 54.32 2.8 54.6 91.0 ;
    END
  END VDD
  PIN VSS
    DIRECTION INOUT ;
    USE GROUND ;
    PORT
      LAYER metal4 ;
      RECT 56.56 2.8 56.84 91.0 ;
    END
  END VSS
  PIN VDD
    DIRECTION INOUT ;
    USE POWER ;
    PORT
      LAYER metal4 ;
      RECT 58.8 2.8 59.08 91.0 ;
    END
  END VDD
  PIN VSS
    DIRECTION INOUT ;
    USE GROUND ;
    PORT
      LAYER metal4 ;
      RECT 61.04 2.8 61.32 91.0 ;
    END
  END VSS
  PIN VDD
    DIRECTION INOUT ;
    USE POWER ;
    PORT
      LAYER metal4 ;
      RECT 63.28 2.8 63.56 91.0 ;
    END
  END VDD
  PIN VSS
    DIRECTION INOUT ;
    USE GROUND ;
    PORT
      LAYER metal4 ;
      RECT 65.52 2.8 65.8 91.0 ;
    END
  END VSS
  PIN VDD
    DIRECTION INOUT ;
    USE POWER ;
    PORT
      LAYER metal4 ;
      RECT 67.76 2.8 68.04 91.0 ;
    END
  END VDD
  PIN VSS
    DIRECTION INOUT ;
    USE GROUND ;
    PORT
      LAYER metal4 ;
      RECT 70.0 2.8 70.28 91.0 ;
    END
  END VSS
  PIN VDD
    DIRECTION INOUT ;
    USE POWER ;
    PORT
      LAYER metal4 ;
      RECT 72.24 2.8 72.52 91.0 ;
    END
  END VDD
  PIN VSS
    DIRECTION INOUT ;
    USE GROUND ;
    PORT
      LAYER metal4 ;
      RECT 74.48 2.8 74.76 91.0 ;
    END
  END VSS
  PIN VDD
    DIRECTION INOUT ;
    USE POWER ;
    PORT
      LAYER metal4 ;
      RECT 76.72 2.8 77.0 91.0 ;
    END
  END VDD
  PIN VSS
    DIRECTION INOUT ;
    USE GROUND ;
    PORT
      LAYER metal4 ;
      RECT 78.96 2.8 79.24 91.0 ;
    END
  END VSS
  PIN VDD
    DIRECTION INOUT ;
    USE POWER ;
    PORT
      LAYER metal4 ;
      RECT 81.2 2.8 81.48 91.0 ;
    END
  END VDD
  PIN VSS
    DIRECTION INOUT ;
    USE GROUND ;
    PORT
      LAYER metal4 ;
      RECT 83.44 2.8 83.72 91.0 ;
    END
  END VSS
  PIN VDD
    DIRECTION INOUT ;
    USE POWER ;
    PORT
      LAYER metal4 ;
      RECT 85.68 2.8 85.96 91.0 ;
    END
  END VDD
  PIN VSS
    DIRECTION INOUT ;
    USE GROUND ;
    PORT
      LAYER metal4 ;
      RECT 87.92 2.8 88.2 91.0 ;
    END
  END VSS
  PIN VDD
    DIRECTION INOUT ;
    USE POWER ;
    PORT
      LAYER metal4 ;
      RECT 90.16 2.8 90.44 91.0 ;
    END
  END VDD
  PIN VSS
    DIRECTION INOUT ;
    USE GROUND ;
    PORT
      LAYER metal4 ;
      RECT 92.4 2.8 92.68 91.0 ;
    END
  END VSS
  PIN VDD
    DIRECTION INOUT ;
    USE POWER ;
    PORT
      LAYER metal4 ;
      RECT 94.64 2.8 94.92 91.0 ;
    END
  END VDD
  PIN VSS
    DIRECTION INOUT ;
    USE GROUND ;
    PORT
      LAYER metal4 ;
      RECT 96.88 2.8 97.16 91.0 ;
    END
  END VSS
  PIN VDD
    DIRECTION INOUT ;
    USE POWER ;
    PORT
      LAYER metal4 ;
      RECT 99.12 2.8 99.4 91.0 ;
    END
  END VDD
  PIN VSS
    DIRECTION INOUT ;
    USE GROUND ;
    PORT
      LAYER metal4 ;
      RECT 101.36 2.8 101.64 91.0 ;
    END
  END VSS
  PIN VDD
    DIRECTION INOUT ;
    USE POWER ;
    PORT
      LAYER metal4 ;
      RECT 103.6 2.8 103.88 91.0 ;
    END
  END VDD
  PIN VSS
    DIRECTION INOUT ;
    USE GROUND ;
    PORT
      LAYER metal4 ;
      RECT 105.84 2.8 106.12 91.0 ;
    END
  END VSS
  PIN VDD
    DIRECTION INOUT ;
    USE POWER ;
    PORT
      LAYER metal4 ;
      RECT 108.08 2.8 108.36 91.0 ;
    END
  END VDD
  PIN VSS
    DIRECTION INOUT ;
    USE GROUND ;
    PORT
      LAYER metal4 ;
      RECT 110.32 2.8 110.6 91.0 ;
    END
  END VSS
  PIN VDD
    DIRECTION INOUT ;
    USE POWER ;
    PORT
      LAYER metal4 ;
      RECT 112.56 2.8 112.84 91.0 ;
    END
  END VDD
  PIN VSS
    DIRECTION INOUT ;
    USE GROUND ;
    PORT
      LAYER metal4 ;
      RECT 114.8 2.8 115.08 91.0 ;
    END
  END VSS
  PIN VDD
    DIRECTION INOUT ;
    USE POWER ;
    PORT
      LAYER metal4 ;
      RECT 117.04 2.8 117.32 91.0 ;
    END
  END VDD
  PIN VSS
    DIRECTION INOUT ;
    USE GROUND ;
    PORT
      LAYER metal4 ;
      RECT 119.28 2.8 119.56 91.0 ;
    END
  END VSS
  PIN VDD
    DIRECTION INOUT ;
    USE POWER ;
    PORT
      LAYER metal4 ;
      RECT 121.52 2.8 121.8 91.0 ;
    END
  END VDD
  PIN VSS
    DIRECTION INOUT ;
    USE GROUND ;
    PORT
      LAYER metal4 ;
      RECT 123.76 2.8 124.04 91.0 ;
    END
  END VSS
  PIN VDD
    DIRECTION INOUT ;
    USE POWER ;
    PORT
      LAYER metal4 ;
      RECT 126.0 2.8 126.28 91.0 ;
    END
  END VDD
  PIN VSS
    DIRECTION INOUT ;
    USE GROUND ;
    PORT
      LAYER metal4 ;
      RECT 128.24 2.8 128.52 91.0 ;
    END
  END VSS
  PIN VDD
    DIRECTION INOUT ;
    USE POWER ;
    PORT
      LAYER metal4 ;
      RECT 130.48 2.8 130.76 91.0 ;
    END
  END VDD
  PIN VSS
    DIRECTION INOUT ;
    USE GROUND ;
    PORT
      LAYER metal4 ;
      RECT 132.72 2.8 133.0 91.0 ;
    END
  END VSS
  PIN VDD
    DIRECTION INOUT ;
    USE POWER ;
    PORT
      LAYER metal4 ;
      RECT 134.96 2.8 135.24 91.0 ;
    END
  END VDD
  PIN VSS
    DIRECTION INOUT ;
    USE GROUND ;
    PORT
      LAYER metal4 ;
      RECT 137.2 2.8 137.48 91.0 ;
    END
  END VSS
  PIN VDD
    DIRECTION INOUT ;
    USE POWER ;
    PORT
      LAYER metal4 ;
      RECT 139.44 2.8 139.72 91.0 ;
    END
  END VDD
  PIN VSS
    DIRECTION INOUT ;
    USE GROUND ;
    PORT
      LAYER metal4 ;
      RECT 141.68 2.8 141.96 91.0 ;
    END
  END VSS
  PIN VDD
    DIRECTION INOUT ;
    USE POWER ;
    PORT
      LAYER metal4 ;
      RECT 143.92 2.8 144.2 91.0 ;
    END
  END VDD
  OBS
    LAYER metal1 ;
    RECT 0 0 149.91 93.8 ;
    LAYER metal2 ;
    RECT 0 0 149.91 93.8 ;
    LAYER metal3 ;
    RECT 0.19 0.0 149.72 2.66 ;
    RECT 0.19 44.1 149.72 93.66 ;
    LAYER metal4 ;
    RECT 0.0 0 2.73 93.8 ;
    RECT 3.15 0 4.97 93.8 ;
    RECT 5.39 0 7.21 93.8 ;
    RECT 7.63 0 9.45 93.8 ;
    RECT 9.87 0 11.69 93.8 ;
    RECT 12.11 0 13.93 93.8 ;
    RECT 14.35 0 16.17 93.8 ;
    RECT 16.59 0 18.41 93.8 ;
    RECT 18.83 0 20.65 93.8 ;
    RECT 21.07 0 22.89 93.8 ;
    RECT 23.31 0 25.13 93.8 ;
    RECT 25.55 0 27.37 93.8 ;
    RECT 27.79 0 29.61 93.8 ;
    RECT 30.03 0 31.85 93.8 ;
    RECT 32.27 0 34.09 93.8 ;
    RECT 34.51 0 36.33 93.8 ;
    RECT 36.75 0 38.57 93.8 ;
    RECT 38.99 0 40.81 93.8 ;
    RECT 41.23 0 43.05 93.8 ;
    RECT 43.47 0 45.29 93.8 ;
    RECT 45.71 0 47.53 93.8 ;
    RECT 47.95 0 49.77 93.8 ;
    RECT 50.19 0 52.01 93.8 ;
    RECT 52.43 0 54.25 93.8 ;
    RECT 54.67 0 56.49 93.8 ;
    RECT 56.91 0 58.73 93.8 ;
    RECT 59.15 0 60.97 93.8 ;
    RECT 61.39 0 63.21 93.8 ;
    RECT 63.63 0 65.45 93.8 ;
    RECT 65.87 0 67.69 93.8 ;
    RECT 68.11 0 69.93 93.8 ;
    RECT 70.35 0 72.17 93.8 ;
    RECT 72.59 0 74.41 93.8 ;
    RECT 74.83 0 76.65 93.8 ;
    RECT 77.07 0 78.89 93.8 ;
    RECT 79.31 0 81.13 93.8 ;
    RECT 81.55 0 83.37 93.8 ;
    RECT 83.79 0 85.61 93.8 ;
    RECT 86.03 0 87.85 93.8 ;
    RECT 88.27 0 90.09 93.8 ;
    RECT 90.51 0 92.33 93.8 ;
    RECT 92.75 0 94.57 93.8 ;
    RECT 94.99 0 96.81 93.8 ;
    RECT 97.23 0 99.05 93.8 ;
    RECT 99.47 0 101.29 93.8 ;
    RECT 101.71 0 103.53 93.8 ;
    RECT 103.95 0 105.77 93.8 ;
    RECT 106.19 0 108.01 93.8 ;
    RECT 108.43 0 110.25 93.8 ;
    RECT 110.67 0 112.49 93.8 ;
    RECT 112.91 0 114.73 93.8 ;
    RECT 115.15 0 116.97 93.8 ;
    RECT 117.39 0 119.21 93.8 ;
    RECT 119.63 0 121.45 93.8 ;
    RECT 121.87 0 123.69 93.8 ;
    RECT 124.11 0 125.93 93.8 ;
    RECT 126.35 0 128.17 93.8 ;
    RECT 128.59 0 130.41 93.8 ;
    RECT 130.83 0 132.65 93.8 ;
    RECT 133.07 0 134.89 93.8 ;
    RECT 135.31 0 137.13 93.8 ;
    RECT 137.55 0 139.37 93.8 ;
    RECT 139.79 0 141.61 93.8 ;
    RECT 142.03 0 143.85 93.8 ;
    RECT 144.27 0 149.84 93.8 ;
  END
END kimi_sram_1024x64_bk
